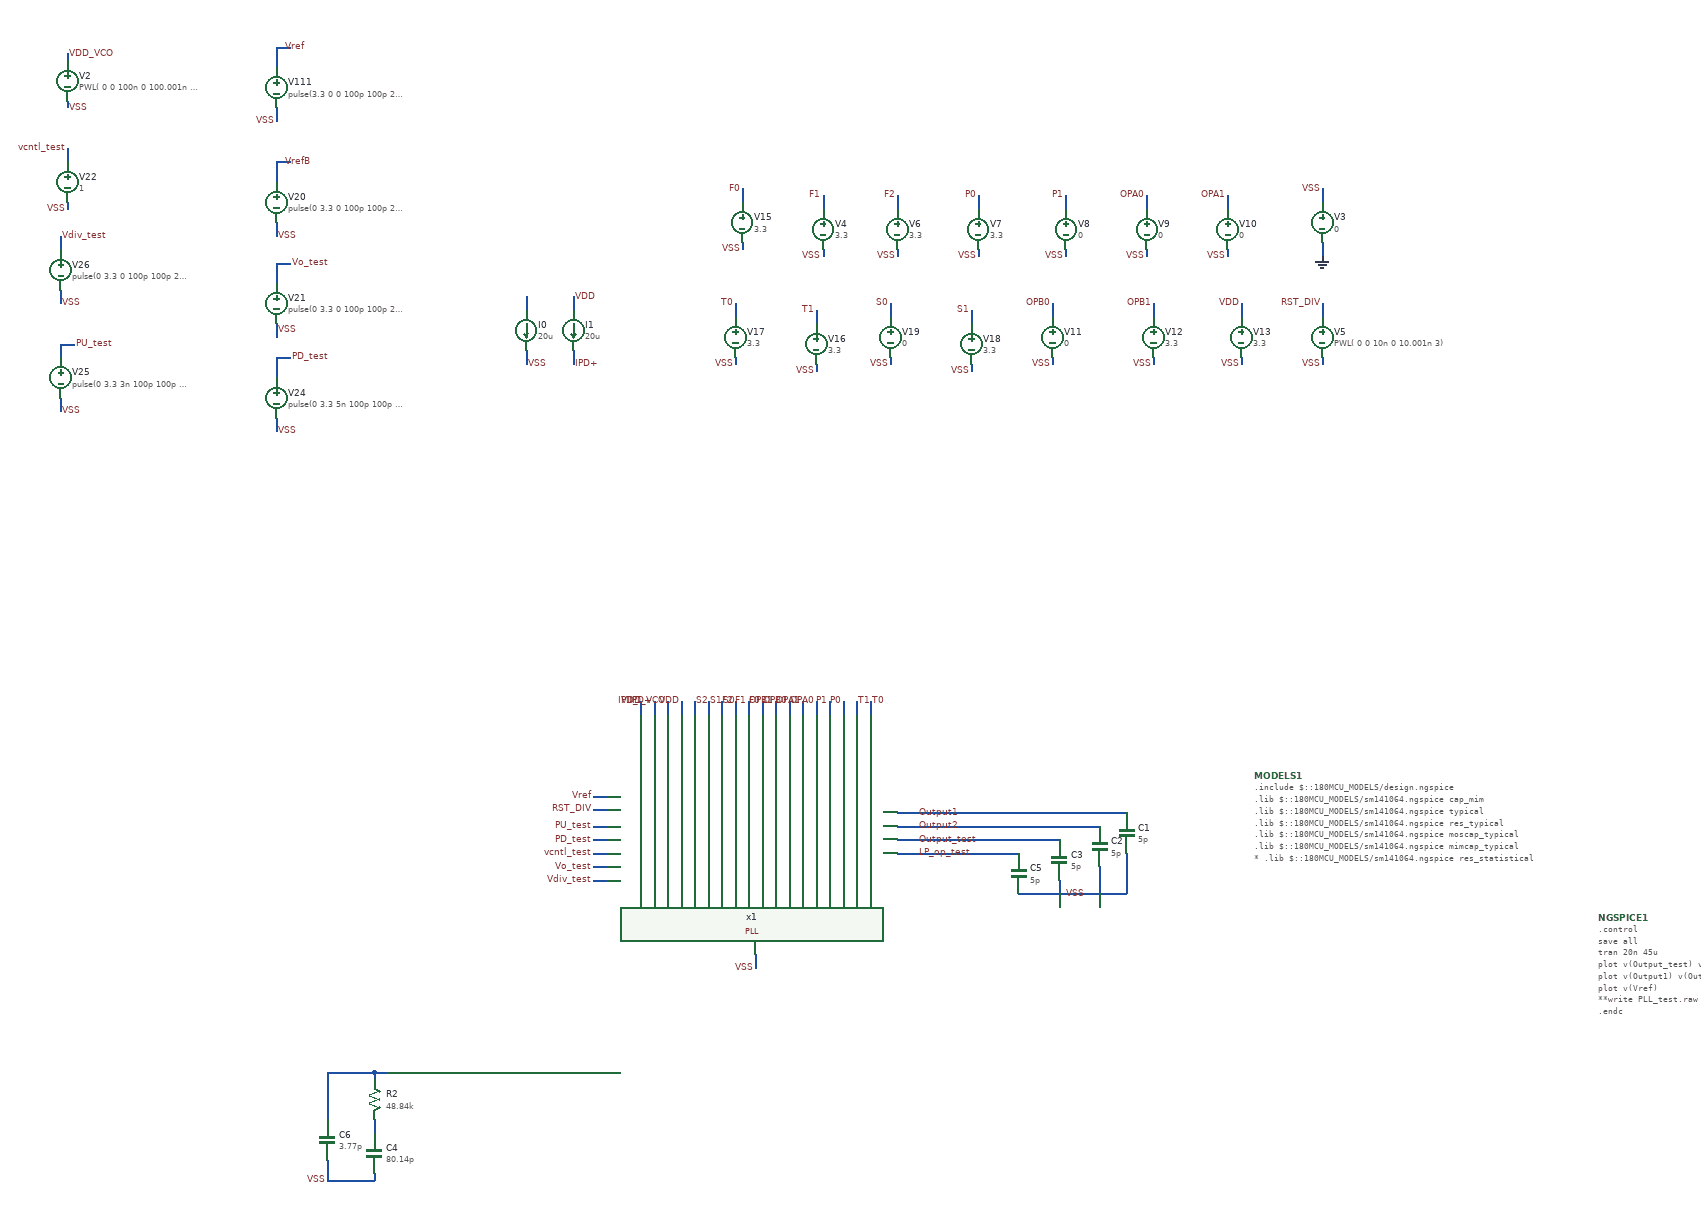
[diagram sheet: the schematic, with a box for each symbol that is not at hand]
v {xschem version=3.1.0 file_version=1.2
}
G {}
K {}
V {}
S {}
E {}
N 450 -150 470 -150 {
lab=Vref}
N 450 -130 470 -130 {
lab=RST_DIV}
N 450 -105 470 -105 {
lab=PU_test}
N 450 -85 470 -85 {
lab=PD_test}
N 450 -65 470 -65 {
lab=vcntl_test}
N 450 -45 470 -45 {
lab=Vo_test}
N 900 -125 920 -125 {
lab=Output1}
N 900 -105 920 -105 {
lab=Output2}
N 900 -85 920 -85 {
lab=Output_test}
N 900 -65 920 -65 {
lab=LP_op_test}
N 520 -290 520 -270 {
lab=IPD_}
N 540 -290 540 -270 {
lab=IPD+}
N 560 -290 560 -270 {
lab=VDD_VCO}
N 580 -290 580 -270 {
lab=VDD}
N 600 -290 600 -270 {
lab=S2}
N 620 -290 620 -270 {
lab=S1}
N 640 -290 640 -270 {
lab=S0}
N 660 -290 660 -270 {
lab=F2}
N 680 -290 680 -270 {
lab=F1}
N 700 -290 700 -270 {
lab=F0}
N -20 -1170 -20 -1150 {
lab=VSS}
N -330 -1180 -330 -1170 {
lab=VSS}
N -20 -1260 0 -1260 {
lab=Vref}
N 1530 -1050 1530 -1030 {
lab=VSS}
N 1530 -970 1530 -950 {
lab=GND}
N 1530 -800 1530 -790 {
lab=VSS}
N 1530 -880 1530 -860 {
lab=RST_DIV}
N 790 -960 790 -950 {
lab=VSS}
N 790 -1040 790 -1020 {
lab=F1}
N 900 -960 900 -950 {
lab=VSS}
N 900 -1040 900 -1020 {
lab=F2}
N 1020 -960 1020 -950 {
lab=VSS}
N 1020 -1040 1020 -1020 {
lab=P0}
N 1150 -960 1150 -950 {
lab=VSS}
N 1150 -1040 1150 -1020 {
lab=P1}
N 1270 -960 1270 -950 {
lab=VSS}
N 1270 -1040 1270 -1020 {
lab=OPA0}
N 1390 -960 1390 -950 {
lab=VSS}
N 1390 -1040 1390 -1020 {
lab=OPA1}
N 1130 -800 1130 -790 {
lab=VSS}
N 1130 -880 1130 -860 {
lab=OPB0}
N 1280 -800 1280 -790 {
lab=VSS}
N 1280 -880 1280 -860 {
lab=OPB1}
N 1410 -800 1410 -790 {
lab=VSS}
N 1410 -880 1410 -860 {
lab=VDD}
N 670 -970 670 -960 {
lab=VSS}
N 670 -1050 670 -1030 {
lab=F0}
N 720 -290 720 -270 {
lab=OPB1}
N 740 -290 740 -270 {
lab=OPB0}
N 760 -290 760 -270 {
lab=OPA1}
N 780 -790 780 -780 {
lab=VSS}
N 780 -870 780 -850 {
lab=T1}
N 660 -800 660 -790 {
lab=VSS}
N 660 -880 660 -860 {
lab=T0}
N 1010 -790 1010 -780 {
lab=VSS}
N 1010 -870 1010 -850 {
lab=S1}
N 890 -800 890 -790 {
lab=VSS}
N 890 -880 890 -860 {
lab=S0}
N -20 -1000 -20 -980 {
lab=VSS}
N -20 -1090 0 -1090 {
lab=VrefB}
N -20 -850 -20 -830 {
lab=VSS}
N -20 -940 0 -940 {
lab=Vo_test}
N -330 -1030 -330 -1020 {
lab=VSS}
N -330 -1110 -330 -1090 {
lab=vcntl_test}
N -20 -710 -20 -690 {
lab=VSS}
N -20 -800 0 -800 {
lab=PD_test}
N -340 -740 -340 -720 {
lab=VSS}
N -340 -820 -320 -820 {
lab=PU_test}
N -340 -900 -340 -880 {
lab=VSS}
N -340 -980 -340 -960 {
lab=Vdiv_test}
N -340 -820 -340 -800 {
lab=PU_test}
N -20 -800 -20 -770 {
lab=PD_test}
N -20 -940 -20 -910 {
lab=Vo_test}
N -20 -1090 -20 -1060 {
lab=VrefB}
N -20 -1260 -20 -1230 {
lab=Vref}
N -330 -1250 -330 -1240 {
lab=VDD_VCO}
N 920 -125 1240 -125 {
lab=Output1}
N 920 -105 1200 -105 {
lab=Output2}
N 920 -85 1140 -85 {
lab=Output_test}
N 1140 -25 1140 -5 {
lab=VSS}
N 1200 -45 1200 -5 {
lab=VSS}
N 1240 -65 1240 -5 {
lab=VSS}
N 920 -65 1080 -65 {
lab=LP_op_test}
N 350 -810 350 -790 {
lab=VSS}
N 420 -810 420 -790 {
lab=IPD+}
N 350 -890 350 -870 {
lab=#net1}
N 420 -890 420 -870 {
lab=VDD}
N 1080 -5 1240 -5 {
lab=VSS}
N 450 -25 470 -25 {
lab=Vdiv_test}
N 690 85 690 105 {
lab=VSS}
N 780 -290 780 -270 {
lab=OPA0}
N 800 -290 800 -270 {
lab=P1}
N 820 -290 820 -270 {
lab=P0}
N 840 -290 840 -270 {
lab=T1}
N 860 -290 860 -270 {
lab=T0}
N 55 390 55 420 {
lab=VSS}
N 55 420 125 420 {
lab=VSS}
N 55 260 55 330 {
lab=#net2}
N 55 260 125 260 {
lab=#net2}
N 125 260 125 270 {
lab=#net2}
N 125 330 125 350 {
lab=#net3}
N 125 410 125 420 {
lab=VSS}
N 125 260 145 260 {
lab=#net2}
C {devices/vsource.sym} -20 -1200 0 0 {name=V111 value="pulse(3.3 0 0 100p 100p 250n 500n)"}
C {devices/vsource.sym} -330 -1210 0 0 {name=V2 value=" PWL( 0 0 100n 0 100.001n 3.3)"}
C {devices/vsource.sym} 1530 -1000 0 0 {name=V3 value=0}
C {devices/lab_wire.sym} 1530 -1050 0 0 {name=p1 sig_type=std_logic lab=VSS}
C {devices/gnd.sym} 1530 -950 0 0 {name=l3 lab=GND}
C {devices/lab_wire.sym} -330 -1250 2 0 {name=p11 sig_type=std_logic lab=VDD_VCO}
C {devices/lab_wire.sym} -10 -1260 2 0 {name=p12 sig_type=std_logic lab=Vref
}
C {devices/lab_wire.sym} 1530 -790 0 0 {name=p13 sig_type=std_logic lab=VSS
}
C {devices/lab_wire.sym} 1530 -880 0 0 {name=p17 sig_type=std_logic lab=RST_DIV}
C {devices/vsource.sym} 1530 -830 0 0 {name=V5 value=" PWL( 0 0 10n 0 10.001n 3)"}
C {devices/lab_wire.sym} 450 -130 0 0 {name=p2 sig_type=std_logic lab=RST_DIV}
C {devices/lab_wire.sym} 690 105 3 0 {name=p5 sig_type=std_logic lab=VSS
}
C {devices/lab_wire.sym} 560 -290 1 0 {name=p7 sig_type=std_logic lab=VDD_VCO}
C {devices/lab_wire.sym} 450 -150 0 0 {name=p8 sig_type=std_logic lab=Vref
}
C {devices/vsource.sym} 790 -990 0 0 {name=V4 value=3.3}
C {devices/lab_wire.sym} 790 -950 0 0 {name=p9 sig_type=std_logic lab=VSS
}
C {devices/lab_wire.sym} 790 -1040 0 0 {name=p10 sig_type=std_logic lab=F1}
C {devices/vsource.sym} 900 -990 0 0 {name=V6 value=3.3}
C {devices/lab_wire.sym} 900 -950 0 0 {name=p14 sig_type=std_logic lab=VSS
}
C {devices/lab_wire.sym} 900 -1040 0 0 {name=p15 sig_type=std_logic lab=F2}
C {devices/vsource.sym} 1020 -990 0 0 {name=V7 value=3.3}
C {devices/lab_wire.sym} 1020 -950 0 0 {name=p16 sig_type=std_logic lab=VSS
}
C {devices/lab_wire.sym} 1020 -1040 0 0 {name=p18 sig_type=std_logic lab=P0}
C {devices/vsource.sym} 1150 -990 0 0 {name=V8 value=0}
C {devices/lab_wire.sym} 1150 -950 0 0 {name=p19 sig_type=std_logic lab=VSS
}
C {devices/lab_wire.sym} 1150 -1040 0 0 {name=p20 sig_type=std_logic lab=P1}
C {devices/vsource.sym} 1270 -990 0 0 {name=V9 value=0}
C {devices/lab_wire.sym} 1270 -950 0 0 {name=p21 sig_type=std_logic lab=VSS
}
C {devices/lab_wire.sym} 1270 -1040 0 0 {name=p22 sig_type=std_logic lab=OPA0}
C {devices/vsource.sym} 1390 -990 0 0 {name=V10 value=0}
C {devices/lab_wire.sym} 1390 -950 0 0 {name=p23 sig_type=std_logic lab=VSS
}
C {devices/lab_wire.sym} 1390 -1040 0 0 {name=p24 sig_type=std_logic lab=OPA1}
C {devices/vsource.sym} 1130 -830 0 0 {name=V11 value=0}
C {devices/lab_wire.sym} 1130 -790 0 0 {name=p25 sig_type=std_logic lab=VSS
}
C {devices/lab_wire.sym} 1130 -880 0 0 {name=p26 sig_type=std_logic lab=OPB0}
C {devices/vsource.sym} 1280 -830 0 0 {name=V12 value=3.3}
C {devices/lab_wire.sym} 1280 -790 0 0 {name=p27 sig_type=std_logic lab=VSS
}
C {devices/lab_wire.sym} 1280 -880 0 0 {name=p28 sig_type=std_logic lab=OPB1}
C {devices/vsource.sym} 1410 -830 0 0 {name=V13 value=3.3}
C {devices/lab_wire.sym} 1410 -790 0 0 {name=p29 sig_type=std_logic lab=VSS
}
C {devices/lab_wire.sym} 1410 -880 0 0 {name=p30 sig_type=std_logic lab=VDD}
C {devices/vsource.sym} 670 -1000 0 0 {name=V15 value=3.3}
C {devices/lab_wire.sym} 670 -960 0 0 {name=p33 sig_type=std_logic lab=VSS
}
C {devices/lab_wire.sym} 670 -1050 0 0 {name=p34 sig_type=std_logic lab=F0}
C {devices/lab_wire.sym} 780 -290 1 0 {name=p35 sig_type=std_logic lab=OPA0}
C {devices/lab_wire.sym} 760 -290 1 0 {name=p36 sig_type=std_logic lab=OPA1}
C {devices/lab_wire.sym} 720 -290 1 0 {name=p37 sig_type=std_logic lab=OPB1}
C {devices/lab_wire.sym} 740 -290 1 0 {name=p38 sig_type=std_logic lab=OPB0}
C {devices/lab_wire.sym} 660 -290 1 0 {name=p39 sig_type=std_logic lab=F2}
C {devices/lab_wire.sym} 680 -290 1 0 {name=p40 sig_type=std_logic lab=F1}
C {devices/lab_wire.sym} 700 -290 1 0 {name=p41 sig_type=std_logic lab=F0}
C {devices/lab_wire.sym} 800 -290 1 0 {name=p42 sig_type=std_logic lab=P1}
C {devices/lab_wire.sym} 820 -290 1 0 {name=p43 sig_type=std_logic lab=P0}
C {devices/lab_wire.sym} 450 -45 0 0 {name=p45 sig_type=std_logic lab=Vo_test
}
C {devices/lab_wire.sym} 450 -65 0 0 {name=p46 sig_type=std_logic lab=vcntl_test
}
C {devices/lab_wire.sym} 450 -85 0 0 {name=p47 sig_type=std_logic lab=PD_test
}
C {devices/lab_wire.sym} 450 -25 0 0 {name=p49 sig_type=std_logic lab=Vdiv_test
}
C {devices/vsource.sym} 780 -820 0 0 {name=V16 value=3.3}
C {devices/lab_wire.sym} 780 -780 0 0 {name=p50 sig_type=std_logic lab=VSS
}
C {devices/lab_wire.sym} 780 -870 0 0 {name=p51 sig_type=std_logic lab=T1}
C {devices/vsource.sym} 660 -830 0 0 {name=V17 value=3.3}
C {devices/lab_wire.sym} 660 -790 0 0 {name=p52 sig_type=std_logic lab=VSS
}
C {devices/lab_wire.sym} 660 -880 0 0 {name=p53 sig_type=std_logic lab=T0}
C {devices/vsource.sym} 1010 -820 0 0 {name=V18 value=3.3}
C {devices/lab_wire.sym} 1010 -780 0 0 {name=p54 sig_type=std_logic lab=VSS
}
C {devices/lab_wire.sym} 1010 -870 0 0 {name=p55 sig_type=std_logic lab=S1}
C {devices/vsource.sym} 890 -830 0 0 {name=V19 value=0}
C {devices/lab_wire.sym} 890 -790 0 0 {name=p56 sig_type=std_logic lab=VSS
}
C {devices/lab_wire.sym} 890 -880 0 0 {name=p57 sig_type=std_logic lab=S0}
C {devices/lab_wire.sym} 860 -290 0 1 {name=p58 sig_type=std_logic lab=T0}
C {devices/lab_wire.sym} 620 -290 0 1 {name=p59 sig_type=std_logic lab=S1}
C {devices/lab_wire.sym} 840 -290 0 1 {name=p60 sig_type=std_logic lab=T1}
C {devices/lab_wire.sym} 640 -290 0 1 {name=p61 sig_type=std_logic lab=S0}
C {devices/lab_wire.sym} 930 -65 2 0 {name=p62 sig_type=std_logic lab=LP_op_test}
C {devices/lab_wire.sym} 930 -85 2 0 {name=p63 sig_type=std_logic lab=Output_test}
C {devices/lab_wire.sym} 930 -125 2 0 {name=p64 sig_type=std_logic lab=Output1}
C {devices/lab_wire.sym} 930 -105 2 0 {name=p66 sig_type=std_logic lab=Output2}
C {devices/vsource.sym} -20 -1030 0 0 {name=V20 value="pulse(0 3.3 0 100p 100p 250n 500n)"}
C {devices/lab_wire.sym} -10 -1090 2 0 {name=p67 sig_type=std_logic lab=VrefB
}
C {devices/vsource.sym} -20 -880 0 0 {name=V21 value="pulse(0 3.3 0 100p 100p 25n 50n)"}
C {devices/lab_wire.sym} 0 -940 2 0 {name=p68 sig_type=std_logic lab=Vo_test
}
C {devices/vsource.sym} -330 -1060 0 0 {name=V22 value=1}
C {devices/lab_wire.sym} -330 -1020 0 0 {name=p69 sig_type=std_logic lab=VSS
}
C {devices/lab_wire.sym} -330 -1110 0 0 {name=p70 sig_type=std_logic lab=vcntl_test
}
C {devices/lab_wire.sym} 450 -105 0 0 {name=p48 sig_type=std_logic lab=PU_test
}
C {devices/vsource.sym} -20 -740 0 0 {name=V24 value="pulse(0 3.3 5n 100p 100p 250n 500n)"}
C {devices/lab_wire.sym} 0 -800 2 0 {name=p72 sig_type=std_logic lab=PD_test
}
C {devices/vsource.sym} -340 -770 0 0 {name=V25 value="pulse(0 3.3 3n 100p 100p 250n 500n)"}
C {devices/lab_wire.sym} -320 -820 2 0 {name=p73 sig_type=std_logic lab=PU_test
}
C {devices/vsource.sym} -340 -930 0 0 {name=V26 value="pulse(0 3.3 0 100p 100p 2.5n 5n)"}
C {devices/lab_wire.sym} -340 -980 2 0 {name=p74 sig_type=std_logic lab=Vdiv_test
}
C {devices/code_shown.sym} 1940 30 0 1 {name=NGSPICE1 only_toplevel=true
value="

.control
save all
tran 20n 45u 
plot v(Output_test) v(LP_op_test)+4
plot v(Output1) v(Output1B)+4 v(Output2)+8
plot v(Vref)

**write PLL_test.raw
.endc
"}
C {devices/lab_wire.sym} -20 -1150 0 0 {name=p75 sig_type=std_logic lab=VSS
}
C {devices/lab_wire.sym} -330 -1170 2 0 {name=p76 sig_type=std_logic lab=VSS
}
C {devices/lab_wire.sym} -20 -980 2 0 {name=p78 sig_type=std_logic lab=VSS
}
C {devices/lab_wire.sym} -20 -840 2 0 {name=p79 sig_type=std_logic lab=VSS
}
C {devices/lab_wire.sym} -340 -880 2 0 {name=p80 sig_type=std_logic lab=VSS
}
C {devices/lab_wire.sym} -340 -720 2 0 {name=p81 sig_type=std_logic lab=VSS
}
C {devices/lab_wire.sym} -20 -690 2 0 {name=p82 sig_type=std_logic lab=VSS
}
C {devices/capa.sym} 1240 -95 0 0 {name=C1
m=1
value=5p
footprint=1206
device="ceramic capacitor"}
C {devices/capa.sym} 1200 -75 0 0 {name=C2
m=1
value=5p
footprint=1206
device="ceramic capacitor"}
C {devices/capa.sym} 1140 -55 0 0 {name=C3
m=1
value=5p
footprint=1206
device="ceramic capacitor"}
C {devices/capa.sym} 1080 -35 0 0 {name=C5
m=1
value=5p
footprint=1206
device="ceramic capacitor"}
C {devices/code_shown.sym} 1430 -180 0 0 {name=MODELS1 only_toplevel=true
format="tcleval( @value )"
value="
.include $::180MCU_MODELS/design.ngspice
.lib $::180MCU_MODELS/sm141064.ngspice cap_mim
.lib $::180MCU_MODELS/sm141064.ngspice typical
.lib $::180MCU_MODELS/sm141064.ngspice res_typical
.lib $::180MCU_MODELS/sm141064.ngspice moscap_typical
.lib $::180MCU_MODELS/sm141064.ngspice mimcap_typical
* .lib $::180MCU_MODELS/sm141064.ngspice res_statistical
"}
C {devices/isource.sym} 350 -840 0 0 {name=I0 value=20u}
C {devices/isource.sym} 420 -840 0 0 {name=I1 value=20u}
C {devices/lab_wire.sym} 520 -290 1 0 {name=p101 sig_type=std_logic lab=IPD_}
C {devices/lab_wire.sym} 420 -790 2 0 {name=p102 sig_type=std_logic lab=IPD+}
C {devices/lab_wire.sym} 350 -790 2 0 {name=p103 sig_type=std_logic lab=VSS}
C {devices/lab_wire.sym} 420 -890 2 0 {name=p104 sig_type=std_logic lab=VDD}
C {devices/lab_wire.sym} 1180 -5 3 0 {name=p3 sig_type=std_logic lab=VSS
}
C {devices/lab_wire.sym} 600 -290 0 1 {name=p4 sig_type=std_logic lab=S2}
C {devices/lab_wire.sym} 580 -290 1 1 {name=p31 sig_type=std_logic lab=VDD}
C {devices/lab_wire.sym} 540 -290 1 0 {name=p6 sig_type=std_logic lab=IPD+}
C {PLL.sym} 660 45 0 0 {name=x1}
C {devices/capa.sym} 125 380 0 0 {name=C4
m=1
value=80.14p
footprint=1206
device="ceramic capacitor"}
C {devices/capa.sym} 55 360 0 0 {name=C6
m=1
value=3.77p
footprint=1206
device="ceramic capacitor"}
C {devices/res.sym} 125 300 0 0 {name=R2
value=48.84k
footprint=1206
device=resistor
m=1}
C {devices/lab_wire.sym} 55 420 2 1 {name=p116 sig_type=std_logic lab=VSS}
